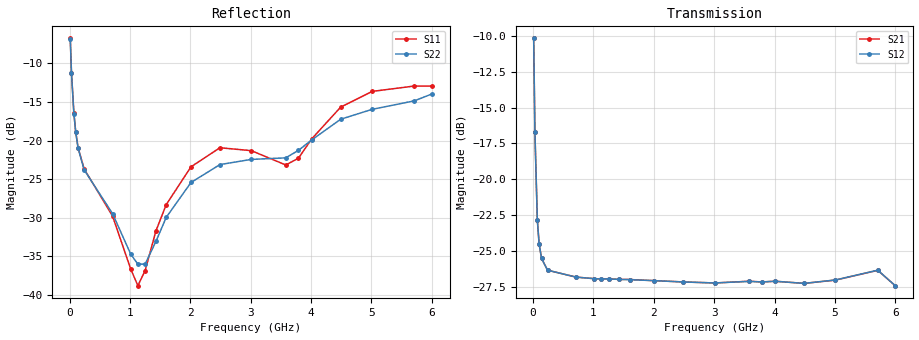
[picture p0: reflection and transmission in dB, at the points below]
! Integrated Device Technology
! Corporate Headquarters
! 6024 Silver Creek Valley Road
! San Jose, CA 95138  USA
! Phone:  1-408-284-8200
! Toll Free:  1-800-223-1366
! Webpage:  http://www.idt.com/
! Timing and RF Division
! 515 Groton Road, Suite 102
! Westford, MA 01886-6024
! Device:  F1951
! Description: 6-bit 0.5 dB Digital Step Attenuator
! Frequency:  100.0 -  4000.00 MHz
! Package:  4x4 mm Thin QFN Plastic Package: 24 pin
! Ports:  2 RF, 6 DC
!  Pin  1  = NC
!  Pin  2  = RF1  =  Port 1
!  Pin  3  = GND
!  Pin  4  = NC
!  Pin  5  = Serial Data Out (SDO)
!  Pin  6  = NC
!  Pin  7  = Reset Bar ( RSTb)
!  Pin  8  = Clock (CLK)
!  Pin  9  = Chip Select Bar (CSb)
!  Pin 10  = NC
!  Pin 11  = Serial Data In (SDI)
!  Pin 12  = NC
!  Pin 13  = NC
!  Pin 14  = VDD
!  Pin 15  = NC
!  Pin 16  = GND
!  Pin 17  = RF2  =  Port 2
!  Pin 18  = NC
!  Pin 19  = GND
!  Pin 20  = GND
!  Pin 21  = GND
!  Pin 22  = GND
!  Pin 23  = GND
!  Pin 24  = GND
! State:  52
! Atten State:  26.0 dB
! Voltage:  +3.30 Volts
! Current:  0.478 mA
! Data:  The device was measured on a F195X evaluation board which has
!  individual transmission lines to the RF pins.  Data was collected
!  de-embedded using a Automatic Fixture Removal [AFR] (Keysight Technologies).
!  The reference plane is the edge of the package pin.
! Misc:  Lot Code  1225BCA
!  Action Tracker AT0399
! Date Measured:  2018-09-13
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# GHz S dB R 50
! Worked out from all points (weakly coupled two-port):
!   600 points, 10 MHz to 6 GHz, reference 50 ohm
!   highest |S21| = -10.18 dB at 10 MHz (marker M1); lowest = -27.4 dB at 6 GHz (marker M2)
!   lowest |S11| = -38.8 dB at 1.13 GHz (marker M3), VSWR 1.02, Z = 48.9 + j0.153 ohm
!   |S11| at or under -10 dB: 23.85 MHz to end of sweep
!   |S22| runs from -36.4 to -6.8 dB; largest |S21 - S12| = 0.00016
!   S11 on the Smith chart (normalised r, x): 10 MHz: 1.77, -1.14; 30 MHz: 1.13, -0.59; 70 MHz: 0.97, -0.30; 1.25 GHz: 0.98, +0.02; 6 GHz: 0.80, +0.36
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0.01  -6.76 -33.6  -10.18 -37.0  -10.18 -37.0  -6.81 -33.6
0.03  -11.22 -62.1  -16.68 -56.6  -16.68 -56.7  -11.26 -62.1
0.07  -16.46 -86.9  -22.81 -47.7  -22.81 -47.7  -16.53 -87.1
0.1  -18.86 -97.7  -24.50 -38.8  -24.50 -38.8  -18.90 -97.8
0.14  -20.93 -108.0  -25.52 -30.8  -25.52 -30.8  -21.00 -107.7
0.24  -23.67 -122.3  -26.34 -21.1  -26.34 -21.0  -23.79 -122.3
0.71  -29.76 -135.1  -26.82 -15.2  -26.82 -15.2  -29.44 -138.1
1.01  -36.60 -155.0  -26.93 -17.0  -26.93 -17.0  -34.67 -152.2
1.13  -38.78 172.2  -26.95 -17.7  -26.95 -17.7  -36.00 -169.4
1.25  -36.83 137.0  -26.95 -18.7  -26.95 -18.7  -35.99 168.2
1.43  -31.67 118.4  -26.98 -20.5  -26.98 -20.5  -33.03 143.7
1.6  -28.28 115.6  -26.99 -22.1  -27.00 -22.1  -29.93 134.5
2.01  -23.39 123.6  -27.07 -26.5  -27.07 -26.5  -25.42 135.2
2.49  -20.92 136.6  -27.16 -31.5  -27.16 -31.5  -23.10 142.4
3.01  -21.30 146.7  -27.23 -36.7  -27.23 -36.6  -22.43 146.0
3.58  -23.15 125.8  -27.11 -42.3  -27.12 -42.3  -22.23 129.0
3.79  -22.28 110.0  -27.16 -44.5  -27.16 -44.4  -21.26 122.1
4.01  -19.77 101.4  -27.11 -46.7  -27.11 -46.6  -19.91 116.7
4.49  -15.66 99.5  -27.26 -51.1  -27.26 -51.1  -17.23 114.8
5.01  -13.63 108.3  -27.03 -53.7  -27.02 -53.7  -15.95 117.3
5.71  -12.93 113.1  -26.35 -65.1  -26.34 -65.1  -14.85 110.1
6  -12.93 107.0  -27.42 -67.3  -27.42 -67.3  -13.96 106.3
